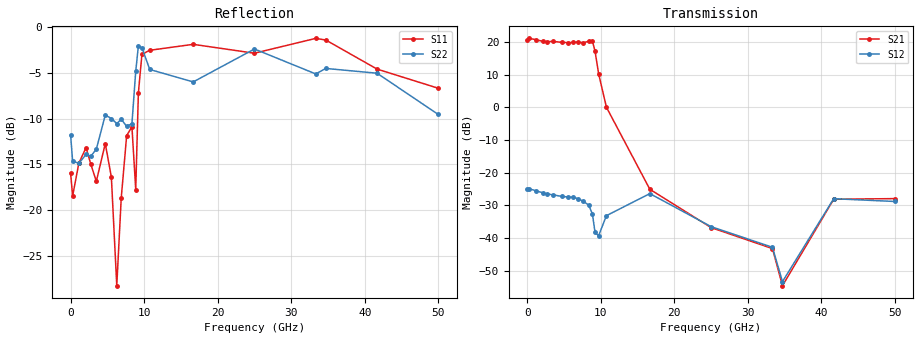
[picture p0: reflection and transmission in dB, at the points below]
!Keysight Technologies,N5245B,MY58422270,A.16.20.02
!Date: Tuesday, March 03, 2026 22:40:26
!Correction: S11(C  2-Port  )
!S21(C  2-Port  )
!S12(C  2-Port  )
!S22(C  2-Port  )
!S2P File: Measurements: S11, S21, S12, S22:
# Hz S  dB  R 50
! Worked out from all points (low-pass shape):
!   3201 points, 10 MHz to 50 GHz, reference 50 ohm
!   highest |S21| = 21.15 dB at 291.2 MHz (marker M1); lowest = -54.6 dB at 34.71 GHz (marker M2)
!   |S21| within 3 dB of the highest: start of sweep to 9.152 GHz
!   lowest |S11| = -28.2 dB at 6.29 GHz (marker M3), VSWR 1.08, Z = 46.3 + j0.578 ohm
!   |S11| at or under -10 dB: start of sweep to 9.133 GHz; 12.81 GHz to 13.86 GHz (1.048 GHz wide, 7.86 % of centre); 45.08 GHz to 49 GHz (3.914 GHz wide, 8.32 % of centre) (the widest 3 of 4)
!   |S22| runs from -15.1 to -1.9 dB; largest |S21 - S12| = 11
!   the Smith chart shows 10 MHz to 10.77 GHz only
!   S11 on the Smith chart (normalised r, x): 10 MHz: 0.86, -0.27; 7.633 GHz: 0.60, -0.05; 9.711 GHz: 0.18, +0.27; 10.77 GHz: 0.40, +1.27
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1e7  -15.92 -108.5  20.70 -170.3  -24.96 11.6  -11.78 145.0
2.911938e8  -18.45 -164.8  21.15 158.2  -24.95 -19.2  -14.65 139.2
1.134775e9  -14.86 178.7  20.76 90.3  -25.44 -80.0  -14.88 39.4
2.118953e9  -13.18 125.5  20.25 15.6  -26.14 -148.6  -13.92 -55.5
2.75945e9  -14.98 72.0  20.15 -32.7  -26.49 165.7  -14.11 -90.4
3.5093e9  -16.85 -28.5  20.20 -91.5  -26.75 109.8  -13.35 -106.8
4.727806e9  -12.73 -164.0  19.94 169.0  -27.25 16.3  -9.62 -150.5
5.555766e9  -16.39 136.5  19.83 99.3  -27.40 -47.8  -10.00 173.5
6.289994e9  -28.23 170.8  19.92 33.7  -27.52 -109.9  -10.55 148.7
6.899247e9  -18.65 -143.0  19.98 -25.1  -27.92 -166.8  -10.08 114.2
7.633475e9  -11.87 -171.3  19.83 -101.2  -28.78 117.6  -10.86 45.5
8.352081e9  -10.90 136.6  20.25 176.1  -29.84 31.3  -10.56 -17.7
8.867603e9  -17.76 -24.5  20.32 95.6  -32.58 -60.8  -4.85 -61.3
9.226906e9  -7.22 -154.8  17.24 30.8  -38.23 -157.0  -2.09 -110.5
9.711184e9  -3.00 148.7  10.36 -34.0  -39.28 73.9  -2.28 -166.4
1.077347e10  -2.56 73.3  0.07 -130.0  -33.13 -37.4  -4.65 100.1
1.667854e10  -1.91 -31.7  -25.06 -165.2  -26.38 -173.5  -6.01 -105.1
2.5005e10  -2.88 175.2  -36.78 -79.8  -36.49 -78.1  -2.42 86.5
3.334708e10  -1.26 42.2  -43.21 57.3  -42.81 62.8  -5.14 -119.5
3.470618e10  -1.44 19.9  -54.57 56.1  -53.34 84.8  -4.54 -155.0
4.167354e10  -4.61 -53.5  -28.10 -66.4  -27.94 -67.8  -5.06 126.0
5e10  -6.70 -57.5  -27.91 -29.4  -28.79 -27.7  -9.56 8.2
